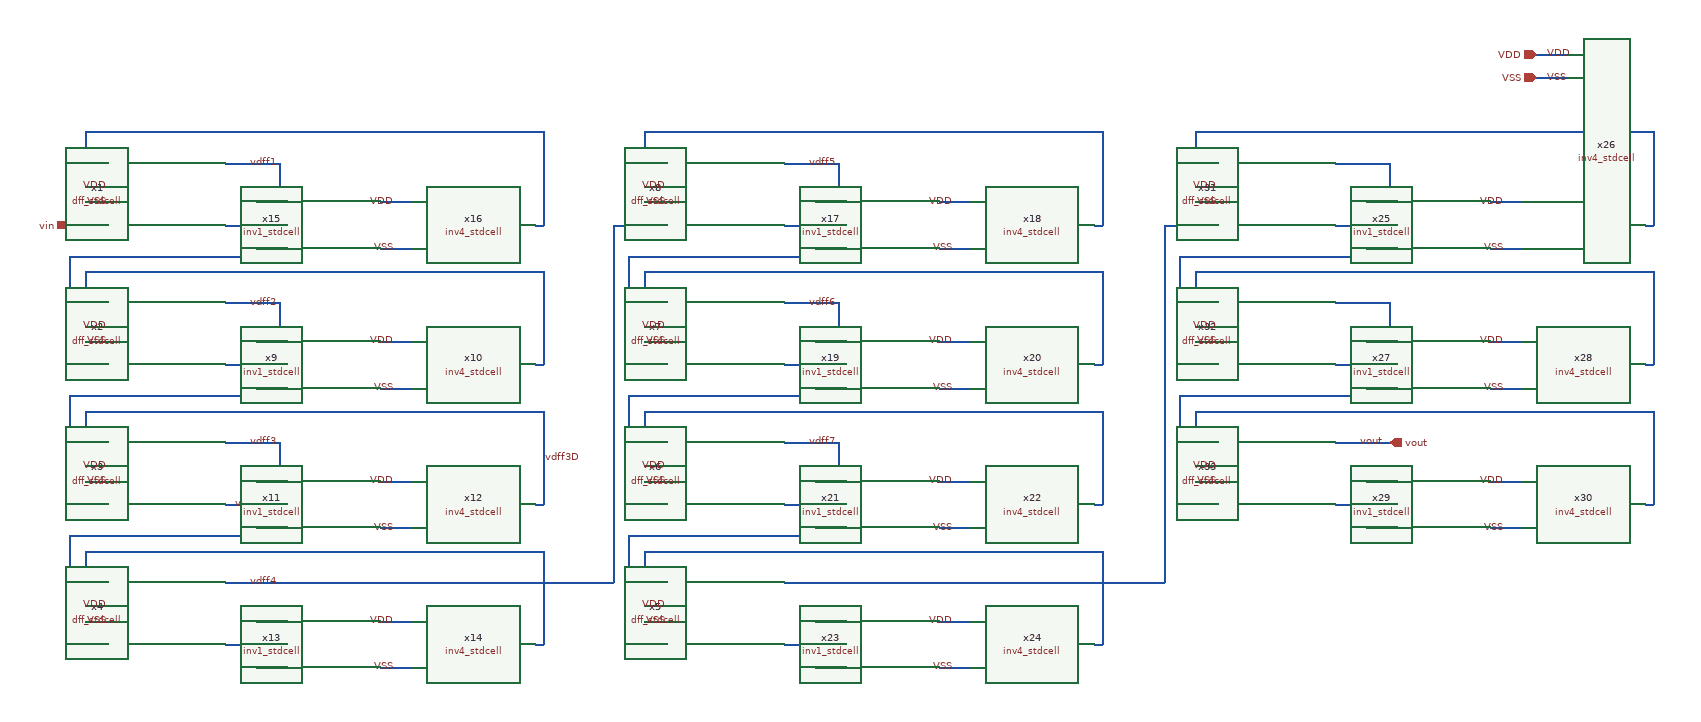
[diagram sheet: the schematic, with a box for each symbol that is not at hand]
v {xschem version=2.9.9 file_version=1.2 }
G {}
K {}
V {}
S {}
E {}
N 60 -730 110 -730 { lab=vin}
N 80 -810 110 -810 { lab=#net1}
N 260 -730 280 -730 { lab=#net2}
N 80 -850 80 -810 { lab=#net1}
N 260 -810 330 -810 { lab=vdff1}
N 60 -550 110 -550 { lab=vdff1}
N 80 -630 110 -630 { lab=#net3}
N 260 -550 280 -550 { lab=#net4}
N 80 -670 80 -630 { lab=#net3}
N 260 -630 330 -630 { lab=vdff2}
N 60 -370 110 -370 { lab=vdff2}
N 80 -450 110 -450 { lab=vdff3D}
N 260 -370 280 -370 { lab=vdff3QB}
N 80 -490 80 -450 { lab=vdff3D}
N 260 -450 330 -450 { lab=vdff3}
N 60 -190 110 -190 { lab=vdff3}
N 80 -270 110 -270 { lab=#net5}
N 260 -190 280 -190 { lab=#net6}
N 80 -310 80 -270 { lab=#net5}
N 260 -270 330 -270 { lab=vdff4}
N 330 -810 330 -690 { lab=vdff1}
N 60 -690 330 -690 { lab=vdff1}
N 60 -690 60 -550 { lab=vdff1}
N 330 -630 330 -510 { lab=vdff2}
N 60 -510 330 -510 { lab=vdff2}
N 60 -510 60 -370 { lab=vdff2}
N 330 -450 330 -330 { lab=vdff3}
N 60 -330 330 -330 { lab=vdff3}
N 60 -330 60 -190 { lab=vdff3}
N 800 -810 830 -810 { lab=#net7}
N 980 -730 1000 -730 { lab=#net8}
N 800 -850 800 -810 { lab=#net7}
N 980 -810 1050 -810 { lab=vdff5}
N 780 -550 830 -550 { lab=vdff5}
N 800 -630 830 -630 { lab=#net9}
N 980 -550 1000 -550 { lab=#net10}
N 800 -670 800 -630 { lab=#net9}
N 980 -630 1050 -630 { lab=vdff6}
N 780 -370 830 -370 { lab=vdff6}
N 800 -450 830 -450 { lab=#net11}
N 980 -370 1000 -370 { lab=#net12}
N 800 -490 800 -450 { lab=#net11}
N 980 -450 1050 -450 { lab=vdff7}
N 780 -190 830 -190 { lab=vdff7}
N 800 -270 830 -270 { lab=#net13}
N 980 -190 1000 -190 { lab=#net14}
N 800 -310 800 -270 { lab=#net13}
N 980 -270 1050 -270 { lab=#net15}
N 1050 -810 1050 -690 { lab=vdff5}
N 780 -690 1050 -690 { lab=vdff5}
N 780 -690 780 -550 { lab=vdff5}
N 1050 -630 1050 -510 { lab=vdff6}
N 780 -510 1050 -510 { lab=vdff6}
N 780 -510 780 -370 { lab=vdff6}
N 1050 -450 1050 -330 { lab=vdff7}
N 780 -330 1050 -330 { lab=vdff7}
N 780 -330 780 -190 { lab=vdff7}
N 330 -270 370 -270 { lab=vdff4}
N 760 -730 830 -730 { lab=vdff4}
N 760 -730 760 -270 { lab=vdff4}
N 280 -730 340 -730 { lab=#net2}
N 80 -850 670 -850 { lab=#net1}
N 670 -850 670 -730 { lab=#net1}
N 660 -730 670 -730 { lab=#net1}
N 280 -550 340 -550 { lab=#net4}
N 80 -670 670 -670 { lab=#net3}
N 670 -670 670 -550 { lab=#net3}
N 660 -550 670 -550 { lab=#net3}
N 280 -370 340 -370 { lab=vdff3QB}
N 80 -490 670 -490 { lab=vdff3D}
N 670 -490 670 -370 { lab=vdff3D}
N 660 -370 670 -370 { lab=vdff3D}
N 280 -190 340 -190 { lab=#net6}
N 80 -310 670 -310 { lab=#net5}
N 670 -310 670 -190 { lab=#net5}
N 660 -190 670 -190 { lab=#net5}
N 1000 -730 1060 -730 { lab=#net8}
N 800 -850 1390 -850 { lab=#net7}
N 1390 -850 1390 -730 { lab=#net7}
N 1380 -730 1390 -730 { lab=#net7}
N 1000 -550 1060 -550 { lab=#net10}
N 800 -670 1390 -670 { lab=#net9}
N 1390 -670 1390 -550 { lab=#net9}
N 1380 -550 1390 -550 { lab=#net9}
N 1000 -370 1060 -370 { lab=#net12}
N 800 -490 1390 -490 { lab=#net11}
N 1390 -490 1390 -370 { lab=#net11}
N 1380 -370 1390 -370 { lab=#net11}
N 1000 -190 1060 -190 { lab=#net14}
N 800 -310 1390 -310 { lab=#net13}
N 1390 -310 1390 -190 { lab=#net13}
N 1380 -190 1390 -190 { lab=#net13}
N 370 -270 760 -270 { lab=vdff4}
N 1510 -810 1540 -810 { lab=#net16}
N 1690 -730 1710 -730 { lab=#net17}
N 1510 -850 1510 -810 { lab=#net16}
N 1690 -810 1760 -810 { lab=#net18}
N 1490 -550 1540 -550 { lab=#net18}
N 1510 -630 1540 -630 { lab=#net19}
N 1690 -550 1710 -550 { lab=#net20}
N 1510 -670 1510 -630 { lab=#net19}
N 1690 -630 1760 -630 { lab=#net21}
N 1490 -370 1540 -370 { lab=#net21}
N 1510 -450 1540 -450 { lab=#net22}
N 1690 -370 1710 -370 { lab=#net23}
N 1510 -490 1510 -450 { lab=#net22}
N 1690 -450 1760 -450 { lab=vout}
N 1760 -810 1760 -690 { lab=#net18}
N 1490 -690 1760 -690 { lab=#net18}
N 1490 -690 1490 -550 { lab=#net18}
N 1760 -630 1760 -510 { lab=#net21}
N 1490 -510 1760 -510 { lab=#net21}
N 1490 -510 1490 -370 { lab=#net21}
N 1470 -730 1540 -730 { lab=#net15}
N 1710 -730 1770 -730 { lab=#net17}
N 1510 -850 2100 -850 { lab=#net16}
N 2100 -850 2100 -730 { lab=#net16}
N 2090 -730 2100 -730 { lab=#net16}
N 1710 -550 1770 -550 { lab=#net20}
N 1510 -670 2100 -670 { lab=#net19}
N 2100 -670 2100 -550 { lab=#net19}
N 2090 -550 2100 -550 { lab=#net19}
N 1710 -370 1770 -370 { lab=#net23}
N 1510 -490 2100 -490 { lab=#net22}
N 2100 -490 2100 -370 { lab=#net22}
N 2090 -370 2100 -370 { lab=#net22}
N 1050 -270 1470 -270 { lab=#net15}
N 1470 -730 1470 -270 { lab=#net15}
N 80 -780 110 -780 { lab=VDD}
N 80 -760 110 -760 { lab=VSS}
N 80 -600 110 -600 { lab=VDD}
N 80 -580 110 -580 { lab=VSS}
N 80 -420 110 -420 { lab=VDD}
N 80 -400 110 -400 { lab=VSS}
N 80 -240 110 -240 { lab=VDD}
N 80 -220 110 -220 { lab=VSS}
N 800 -240 830 -240 { lab=VDD}
N 800 -220 830 -220 { lab=VSS}
N 800 -420 830 -420 { lab=VDD}
N 800 -400 830 -400 { lab=VSS}
N 800 -600 830 -600 { lab=VDD}
N 800 -580 830 -580 { lab=VSS}
N 800 -780 830 -780 { lab=VDD}
N 800 -760 830 -760 { lab=VSS}
N 1510 -780 1540 -780 { lab=VDD}
N 1510 -760 1540 -760 { lab=VSS}
N 1510 -600 1540 -600 { lab=VDD}
N 1510 -580 1540 -580 { lab=VSS}
N 1510 -420 1540 -420 { lab=VDD}
N 1510 -400 1540 -400 { lab=VSS}
N 1950 -950 1990 -950 { lab=VDD}
N 1950 -920 1990 -920 { lab=VSS}
N 300 -760 340 -760 { lab=VDD}
N 300 -700 340 -700 { lab=VSS}
N 460 -760 500 -760 { lab=VDD}
N 460 -700 500 -700 { lab=VSS}
N 300 -580 340 -580 { lab=VDD}
N 300 -520 340 -520 { lab=VSS}
N 460 -580 500 -580 { lab=VDD}
N 460 -520 500 -520 { lab=VSS}
N 300 -400 340 -400 { lab=VDD}
N 300 -340 340 -340 { lab=VSS}
N 460 -400 500 -400 { lab=VDD}
N 460 -340 500 -340 { lab=VSS}
N 300 -220 340 -220 { lab=VDD}
N 300 -160 340 -160 { lab=VSS}
N 460 -220 500 -220 { lab=VDD}
N 460 -160 500 -160 { lab=VSS}
N 1020 -220 1060 -220 { lab=VDD}
N 1020 -160 1060 -160 { lab=VSS}
N 1180 -220 1220 -220 { lab=VDD}
N 1180 -160 1220 -160 { lab=VSS}
N 1020 -400 1060 -400 { lab=VDD}
N 1020 -340 1060 -340 { lab=VSS}
N 1180 -400 1220 -400 { lab=VDD}
N 1180 -340 1220 -340 { lab=VSS}
N 1020 -580 1060 -580 { lab=VDD}
N 1020 -520 1060 -520 { lab=VSS}
N 1180 -580 1220 -580 { lab=VDD}
N 1180 -520 1220 -520 { lab=VSS}
N 1020 -760 1060 -760 { lab=VDD}
N 1020 -700 1060 -700 { lab=VSS}
N 1180 -760 1220 -760 { lab=VDD}
N 1180 -700 1220 -700 { lab=VSS}
N 1730 -760 1770 -760 { lab=VDD}
N 1730 -700 1770 -700 { lab=VSS}
N 1890 -760 1930 -760 { lab=VDD}
N 1890 -700 1930 -700 { lab=VSS}
N 1730 -580 1770 -580 { lab=VDD}
N 1730 -520 1770 -520 { lab=VSS}
N 1890 -580 1930 -580 { lab=VDD}
N 1890 -520 1930 -520 { lab=VSS}
N 1730 -400 1770 -400 { lab=VDD}
N 1730 -340 1770 -340 { lab=VSS}
N 1890 -400 1930 -400 { lab=VDD}
N 1890 -340 1930 -340 { lab=VSS}
C {devices/title.sym} 160 -30 0 0 {name=l1 author="Nikhil Poole"}
C {devices/lab_wire.sym} 290 -810 0 1 {name=l6 sig_type=std_logic lab=vdff1}
C {devices/lab_wire.sym} 290 -630 0 1 {name=l9 sig_type=std_logic lab=vdff2}
C {devices/lab_wire.sym} 290 -450 0 1 {name=l11 sig_type=std_logic lab=vdff3}
C {devices/lab_wire.sym} 290 -270 0 1 {name=l16 sig_type=std_logic lab=vdff4}
C {devices/lab_wire.sym} 1010 -810 0 1 {name=l7 sig_type=std_logic lab=vdff5}
C {devices/lab_wire.sym} 1010 -630 0 1 {name=l10 sig_type=std_logic lab=vdff6}
C {devices/lab_wire.sym} 1010 -450 0 1 {name=l15 sig_type=std_logic lab=vdff7}
C {devices/lab_wire.sym} 270 -370 0 1 {name=l17 sig_type=std_logic lab=vdff3QB}
C {devices/lab_wire.sym} 670 -430 0 1 {name=l19 sig_type=std_logic lab=vdff3D}
C {devices/lab_wire.sym} 1720 -450 0 1 {name=l2 sig_type=std_logic lab=vout}
C {devices/ipin.sym} 60 -730 0 0 {name=p1 lab=vin}
C {devices/opin.sym} 1760 -450 0 0 {name=p5 lab=vout}
C {/home/users/nhpoole/ee272b/ee272b_mixed_signal_mmwave_accelerator/designs/dff_stdcell.sym} 180 -760 0 0 {name=x1}
C {devices/lab_wire.sym} 110 -780 0 0 {name=l3 sig_type=std_logic lab=VDD}
C {devices/lab_wire.sym} 110 -760 0 0 {name=l4 sig_type=std_logic lab=VSS}
C {/home/users/nhpoole/ee272b/ee272b_mixed_signal_mmwave_accelerator/designs/dff_stdcell.sym} 180 -580 0 0 {name=x2}
C {devices/lab_wire.sym} 110 -600 0 0 {name=l5 sig_type=std_logic lab=VDD}
C {devices/lab_wire.sym} 110 -580 0 0 {name=l8 sig_type=std_logic lab=VSS}
C {/home/users/nhpoole/ee272b/ee272b_mixed_signal_mmwave_accelerator/designs/dff_stdcell.sym} 180 -400 0 0 {name=x3}
C {devices/lab_wire.sym} 110 -420 0 0 {name=l12 sig_type=std_logic lab=VDD}
C {devices/lab_wire.sym} 110 -400 0 0 {name=l13 sig_type=std_logic lab=VSS}
C {/home/users/nhpoole/ee272b/ee272b_mixed_signal_mmwave_accelerator/designs/dff_stdcell.sym} 180 -220 0 0 {name=x4}
C {devices/lab_wire.sym} 110 -240 0 0 {name=l14 sig_type=std_logic lab=VDD}
C {devices/lab_wire.sym} 110 -220 0 0 {name=l18 sig_type=std_logic lab=VSS}
C {/home/users/nhpoole/ee272b/ee272b_mixed_signal_mmwave_accelerator/designs/dff_stdcell.sym} 900 -220 0 0 {name=x5}
C {devices/lab_wire.sym} 830 -240 0 0 {name=l20 sig_type=std_logic lab=VDD}
C {devices/lab_wire.sym} 830 -220 0 0 {name=l21 sig_type=std_logic lab=VSS}
C {/home/users/nhpoole/ee272b/ee272b_mixed_signal_mmwave_accelerator/designs/dff_stdcell.sym} 900 -400 0 0 {name=x6}
C {devices/lab_wire.sym} 830 -420 0 0 {name=l22 sig_type=std_logic lab=VDD}
C {devices/lab_wire.sym} 830 -400 0 0 {name=l23 sig_type=std_logic lab=VSS}
C {/home/users/nhpoole/ee272b/ee272b_mixed_signal_mmwave_accelerator/designs/dff_stdcell.sym} 900 -580 0 0 {name=x7}
C {devices/lab_wire.sym} 830 -600 0 0 {name=l24 sig_type=std_logic lab=VDD}
C {devices/lab_wire.sym} 830 -580 0 0 {name=l25 sig_type=std_logic lab=VSS}
C {/home/users/nhpoole/ee272b/ee272b_mixed_signal_mmwave_accelerator/designs/dff_stdcell.sym} 900 -760 0 0 {name=x8}
C {devices/lab_wire.sym} 830 -780 0 0 {name=l26 sig_type=std_logic lab=VDD}
C {devices/lab_wire.sym} 830 -760 0 0 {name=l27 sig_type=std_logic lab=VSS}
C {/home/users/nhpoole/ee272b/ee272b_mixed_signal_mmwave_accelerator/designs/dff_stdcell.sym} 1610 -760 0 0 {name=x31}
C {devices/lab_wire.sym} 1540 -780 0 0 {name=l28 sig_type=std_logic lab=VDD}
C {devices/lab_wire.sym} 1540 -760 0 0 {name=l29 sig_type=std_logic lab=VSS}
C {/home/users/nhpoole/ee272b/ee272b_mixed_signal_mmwave_accelerator/designs/dff_stdcell.sym} 1610 -580 0 0 {name=x32}
C {devices/lab_wire.sym} 1540 -600 0 0 {name=l30 sig_type=std_logic lab=VDD}
C {devices/lab_wire.sym} 1540 -580 0 0 {name=l31 sig_type=std_logic lab=VSS}
C {/home/users/nhpoole/ee272b/ee272b_mixed_signal_mmwave_accelerator/designs/dff_stdcell.sym} 1610 -400 0 0 {name=x33}
C {devices/lab_wire.sym} 1540 -420 0 0 {name=l32 sig_type=std_logic lab=VDD}
C {devices/lab_wire.sym} 1540 -400 0 0 {name=l33 sig_type=std_logic lab=VSS}
C {devices/ipin.sym} 1950 -950 0 0 {name=p2 lab=VDD}
C {devices/ipin.sym} 1950 -920 0 0 {name=p3 lab=VSS}
C {devices/lab_wire.sym} 1960 -950 0 1 {name=l34 sig_type=std_logic lab=VDD}
C {devices/lab_wire.sym} 1960 -920 0 1 {name=l35 sig_type=std_logic lab=VSS}
C {devices/lab_wire.sym} 320 -760 0 0 {name=l36 sig_type=std_logic lab=VDD}
C {devices/lab_wire.sym} 320 -700 0 0 {name=l37 sig_type=std_logic lab=VSS}
C {devices/lab_wire.sym} 480 -760 0 0 {name=l38 sig_type=std_logic lab=VDD}
C {devices/lab_wire.sym} 480 -700 0 0 {name=l39 sig_type=std_logic lab=VSS}
C {devices/lab_wire.sym} 320 -580 0 0 {name=l40 sig_type=std_logic lab=VDD}
C {devices/lab_wire.sym} 480 -580 0 0 {name=l41 sig_type=std_logic lab=VDD}
C {devices/lab_wire.sym} 480 -520 0 0 {name=l42 sig_type=std_logic lab=VSS}
C {devices/lab_wire.sym} 320 -520 0 0 {name=l43 sig_type=std_logic lab=VSS}
C {devices/lab_wire.sym} 320 -400 0 0 {name=l44 sig_type=std_logic lab=VDD}
C {devices/lab_wire.sym} 480 -400 0 0 {name=l45 sig_type=std_logic lab=VDD}
C {devices/lab_wire.sym} 480 -340 0 0 {name=l46 sig_type=std_logic lab=VSS}
C {devices/lab_wire.sym} 320 -340 0 0 {name=l47 sig_type=std_logic lab=VSS}
C {devices/lab_wire.sym} 320 -220 0 0 {name=l48 sig_type=std_logic lab=VDD}
C {devices/lab_wire.sym} 480 -220 0 0 {name=l49 sig_type=std_logic lab=VDD}
C {devices/lab_wire.sym} 480 -160 0 0 {name=l50 sig_type=std_logic lab=VSS}
C {devices/lab_wire.sym} 320 -160 0 0 {name=l51 sig_type=std_logic lab=VSS}
C {devices/lab_wire.sym} 1040 -220 0 0 {name=l52 sig_type=std_logic lab=VDD}
C {devices/lab_wire.sym} 1200 -220 0 0 {name=l53 sig_type=std_logic lab=VDD}
C {devices/lab_wire.sym} 1200 -160 0 0 {name=l54 sig_type=std_logic lab=VSS}
C {devices/lab_wire.sym} 1040 -160 0 0 {name=l55 sig_type=std_logic lab=VSS}
C {devices/lab_wire.sym} 1040 -400 0 0 {name=l56 sig_type=std_logic lab=VDD}
C {devices/lab_wire.sym} 1200 -400 0 0 {name=l57 sig_type=std_logic lab=VDD}
C {devices/lab_wire.sym} 1200 -340 0 0 {name=l58 sig_type=std_logic lab=VSS}
C {devices/lab_wire.sym} 1040 -340 0 0 {name=l59 sig_type=std_logic lab=VSS}
C {devices/lab_wire.sym} 1040 -580 0 0 {name=l60 sig_type=std_logic lab=VDD}
C {devices/lab_wire.sym} 1200 -580 0 0 {name=l61 sig_type=std_logic lab=VDD}
C {devices/lab_wire.sym} 1200 -520 0 0 {name=l62 sig_type=std_logic lab=VSS}
C {devices/lab_wire.sym} 1040 -520 0 0 {name=l63 sig_type=std_logic lab=VSS}
C {devices/lab_wire.sym} 1040 -760 0 0 {name=l64 sig_type=std_logic lab=VDD}
C {devices/lab_wire.sym} 1200 -760 0 0 {name=l65 sig_type=std_logic lab=VDD}
C {devices/lab_wire.sym} 1200 -700 0 0 {name=l66 sig_type=std_logic lab=VSS}
C {devices/lab_wire.sym} 1040 -700 0 0 {name=l67 sig_type=std_logic lab=VSS}
C {devices/lab_wire.sym} 1750 -760 0 0 {name=l68 sig_type=std_logic lab=VDD}
C {devices/lab_wire.sym} 1910 -760 0 0 {name=l69 sig_type=std_logic lab=VDD}
C {devices/lab_wire.sym} 1910 -700 0 0 {name=l70 sig_type=std_logic lab=VSS}
C {devices/lab_wire.sym} 1750 -700 0 0 {name=l71 sig_type=std_logic lab=VSS}
C {devices/lab_wire.sym} 1750 -580 0 0 {name=l72 sig_type=std_logic lab=VDD}
C {devices/lab_wire.sym} 1910 -580 0 0 {name=l73 sig_type=std_logic lab=VDD}
C {devices/lab_wire.sym} 1910 -520 0 0 {name=l74 sig_type=std_logic lab=VSS}
C {devices/lab_wire.sym} 1750 -520 0 0 {name=l75 sig_type=std_logic lab=VSS}
C {devices/lab_wire.sym} 1750 -400 0 0 {name=l76 sig_type=std_logic lab=VDD}
C {devices/lab_wire.sym} 1910 -400 0 0 {name=l77 sig_type=std_logic lab=VDD}
C {devices/lab_wire.sym} 1910 -340 0 0 {name=l78 sig_type=std_logic lab=VSS}
C {devices/lab_wire.sym} 1750 -340 0 0 {name=l79 sig_type=std_logic lab=VSS}
C {/home/users/nhpoole/ee272b/ee272b_mixed_signal_mmwave_accelerator/designs/inv1_stdcell.sym} 390 -730 0 0 {name=x15}
C {/home/users/nhpoole/ee272b/ee272b_mixed_signal_mmwave_accelerator/designs/inv4_stdcell.sym} 550 -730 0 0 {name=x16}
C {/home/users/nhpoole/ee272b/ee272b_mixed_signal_mmwave_accelerator/designs/inv1_stdcell.sym} 390 -550 0 0 {name=x9}
C {/home/users/nhpoole/ee272b/ee272b_mixed_signal_mmwave_accelerator/designs/inv4_stdcell.sym} 550 -550 0 0 {name=x10}
C {/home/users/nhpoole/ee272b/ee272b_mixed_signal_mmwave_accelerator/designs/inv1_stdcell.sym} 390 -370 0 0 {name=x11}
C {/home/users/nhpoole/ee272b/ee272b_mixed_signal_mmwave_accelerator/designs/inv4_stdcell.sym} 550 -370 0 0 {name=x12}
C {/home/users/nhpoole/ee272b/ee272b_mixed_signal_mmwave_accelerator/designs/inv1_stdcell.sym} 390 -190 0 0 {name=x13}
C {/home/users/nhpoole/ee272b/ee272b_mixed_signal_mmwave_accelerator/designs/inv4_stdcell.sym} 550 -190 0 0 {name=x14}
C {/home/users/nhpoole/ee272b/ee272b_mixed_signal_mmwave_accelerator/designs/inv1_stdcell.sym} 1110 -730 0 0 {name=x17}
C {/home/users/nhpoole/ee272b/ee272b_mixed_signal_mmwave_accelerator/designs/inv4_stdcell.sym} 1270 -730 0 0 {name=x18}
C {/home/users/nhpoole/ee272b/ee272b_mixed_signal_mmwave_accelerator/designs/inv1_stdcell.sym} 1110 -550 0 0 {name=x19}
C {/home/users/nhpoole/ee272b/ee272b_mixed_signal_mmwave_accelerator/designs/inv4_stdcell.sym} 1270 -550 0 0 {name=x20}
C {/home/users/nhpoole/ee272b/ee272b_mixed_signal_mmwave_accelerator/designs/inv1_stdcell.sym} 1110 -370 0 0 {name=x21}
C {/home/users/nhpoole/ee272b/ee272b_mixed_signal_mmwave_accelerator/designs/inv4_stdcell.sym} 1270 -370 0 0 {name=x22}
C {/home/users/nhpoole/ee272b/ee272b_mixed_signal_mmwave_accelerator/designs/inv1_stdcell.sym} 1110 -190 0 0 {name=x23}
C {/home/users/nhpoole/ee272b/ee272b_mixed_signal_mmwave_accelerator/designs/inv4_stdcell.sym} 1270 -190 0 0 {name=x24}
C {/home/users/nhpoole/ee272b/ee272b_mixed_signal_mmwave_accelerator/designs/inv1_stdcell.sym} 1820 -730 0 0 {name=x25}
C {/home/users/nhpoole/ee272b/ee272b_mixed_signal_mmwave_accelerator/designs/inv4_stdcell.sym} 1980 -730 0 0 {name=x26}
C {/home/users/nhpoole/ee272b/ee272b_mixed_signal_mmwave_accelerator/designs/inv1_stdcell.sym} 1820 -550 0 0 {name=x27}
C {/home/users/nhpoole/ee272b/ee272b_mixed_signal_mmwave_accelerator/designs/inv4_stdcell.sym} 1980 -550 0 0 {name=x28}
C {/home/users/nhpoole/ee272b/ee272b_mixed_signal_mmwave_accelerator/designs/inv1_stdcell.sym} 1820 -370 0 0 {name=x29}
C {/home/users/nhpoole/ee272b/ee272b_mixed_signal_mmwave_accelerator/designs/inv4_stdcell.sym} 1980 -370 0 0 {name=x30}
